One B-rep face of a CAD part: STEP entity #3053.
In plain terms, the planar face has unit normal (0, 0, -1).
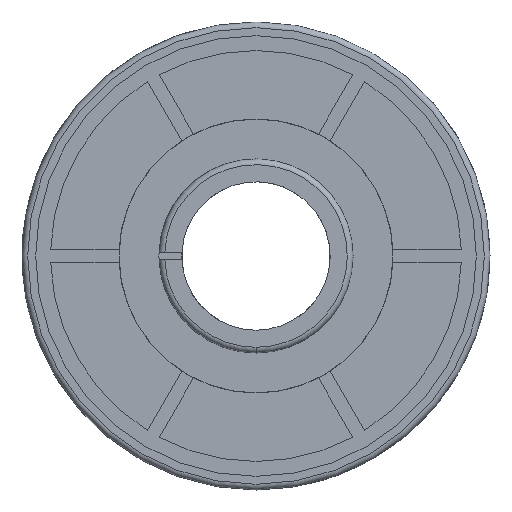
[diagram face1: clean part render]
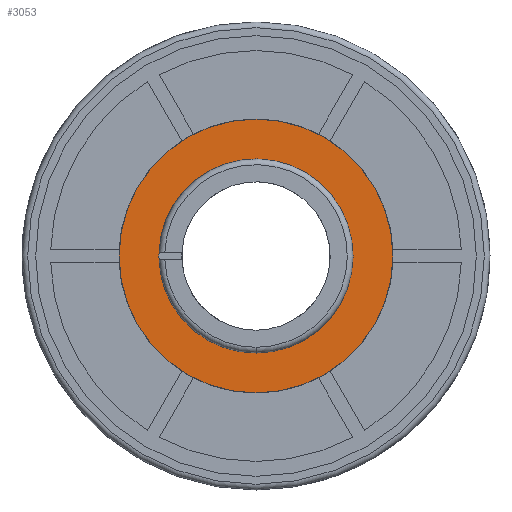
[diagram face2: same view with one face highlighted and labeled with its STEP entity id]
Its self-contained STEP definition (entity closure, numbers rounded to 3 decimals):
#1938 = CYLINDRICAL_SURFACE('',#1939,8.5);
#1939 = AXIS2_PLACEMENT_3D('',#1940,#1941,#1942);
#1940 = CARTESIAN_POINT('',(0.,0.,-9.6));
#1941 = DIRECTION('',(0.,0.,1.));
#1942 = DIRECTION('',(1.,0.,-0.));
#2235 = VERTEX_POINT('',#2236);
#2236 = CARTESIAN_POINT('',(8.5,0.,0.));
#2305 = EDGE_CURVE('',#2235,#2235,#2306,.T.);
#2306 = SURFACE_CURVE('',#2307,(#2312,#2319),.PCURVE_S1.);
#2307 = CIRCLE('',#2308,8.5);
#2308 = AXIS2_PLACEMENT_3D('',#2309,#2310,#2311);
#2309 = CARTESIAN_POINT('',(0.,0.,0.));
#2310 = DIRECTION('',(0.,0.,1.));
#2311 = DIRECTION('',(1.,0.,-0.));
#2312 = PCURVE('',#1938,#2313);
#2313 = DEFINITIONAL_REPRESENTATION('',(#2314),#2318);
#2314 = LINE('',#2315,#2316);
#2315 = CARTESIAN_POINT('',(0.,9.6));
#2316 = VECTOR('',#2317,1.);
#2317 = DIRECTION('',(1.,0.));
#2318 = ( GEOMETRIC_REPRESENTATION_CONTEXT(2) 
PARAMETRIC_REPRESENTATION_CONTEXT() REPRESENTATION_CONTEXT('2D SPACE',''
  ) );
#2319 = PCURVE('',#2320,#2325);
#2320 = PLANE('',#2321);
#2321 = AXIS2_PLACEMENT_3D('',#2322,#2323,#2324);
#2322 = CARTESIAN_POINT('',(0.,0.,0.));
#2323 = DIRECTION('',(0.,0.,1.));
#2324 = DIRECTION('',(1.,0.,-0.));
#2325 = DEFINITIONAL_REPRESENTATION('',(#2326),#2330);
#2326 = CIRCLE('',#2327,8.5);
#2327 = AXIS2_PLACEMENT_2D('',#2328,#2329);
#2328 = CARTESIAN_POINT('',(0.,0.));
#2329 = DIRECTION('',(1.,0.));
#2330 = ( GEOMETRIC_REPRESENTATION_CONTEXT(2) 
PARAMETRIC_REPRESENTATION_CONTEXT() REPRESENTATION_CONTEXT('2D SPACE',''
  ) );
#2451 = CYLINDRICAL_SURFACE('',#2452,12.);
#2452 = AXIS2_PLACEMENT_3D('',#2453,#2454,#2455);
#2453 = CARTESIAN_POINT('',(0.,0.,-2.));
#2454 = DIRECTION('',(0.,0.,1.));
#2455 = DIRECTION('',(1.,0.,-0.));
#3053 = ADVANCED_FACE('',(#3054,#3080),#2320,.F.);
#3054 = FACE_BOUND('',#3055,.F.);
#3055 = EDGE_LOOP('',(#3056));
#3056 = ORIENTED_EDGE('',*,*,#3057,.T.);
#3057 = EDGE_CURVE('',#3058,#3058,#3060,.T.);
#3058 = VERTEX_POINT('',#3059);
#3059 = CARTESIAN_POINT('',(12.,0.,0.));
#3060 = SURFACE_CURVE('',#3061,(#3066,#3073),.PCURVE_S1.);
#3061 = CIRCLE('',#3062,12.);
#3062 = AXIS2_PLACEMENT_3D('',#3063,#3064,#3065);
#3063 = CARTESIAN_POINT('',(0.,0.,0.));
#3064 = DIRECTION('',(0.,0.,1.));
#3065 = DIRECTION('',(1.,0.,-0.));
#3066 = PCURVE('',#2320,#3067);
#3067 = DEFINITIONAL_REPRESENTATION('',(#3068),#3072);
#3068 = CIRCLE('',#3069,12.);
#3069 = AXIS2_PLACEMENT_2D('',#3070,#3071);
#3070 = CARTESIAN_POINT('',(0.,0.));
#3071 = DIRECTION('',(1.,0.));
#3072 = ( GEOMETRIC_REPRESENTATION_CONTEXT(2) 
PARAMETRIC_REPRESENTATION_CONTEXT() REPRESENTATION_CONTEXT('2D SPACE',''
  ) );
#3073 = PCURVE('',#2451,#3074);
#3074 = DEFINITIONAL_REPRESENTATION('',(#3075),#3079);
#3075 = LINE('',#3076,#3077);
#3076 = CARTESIAN_POINT('',(0.,2.));
#3077 = VECTOR('',#3078,1.);
#3078 = DIRECTION('',(1.,0.));
#3079 = ( GEOMETRIC_REPRESENTATION_CONTEXT(2) 
PARAMETRIC_REPRESENTATION_CONTEXT() REPRESENTATION_CONTEXT('2D SPACE',''
  ) );
#3080 = FACE_BOUND('',#3081,.F.);
#3081 = EDGE_LOOP('',(#3082));
#3082 = ORIENTED_EDGE('',*,*,#2305,.F.);
